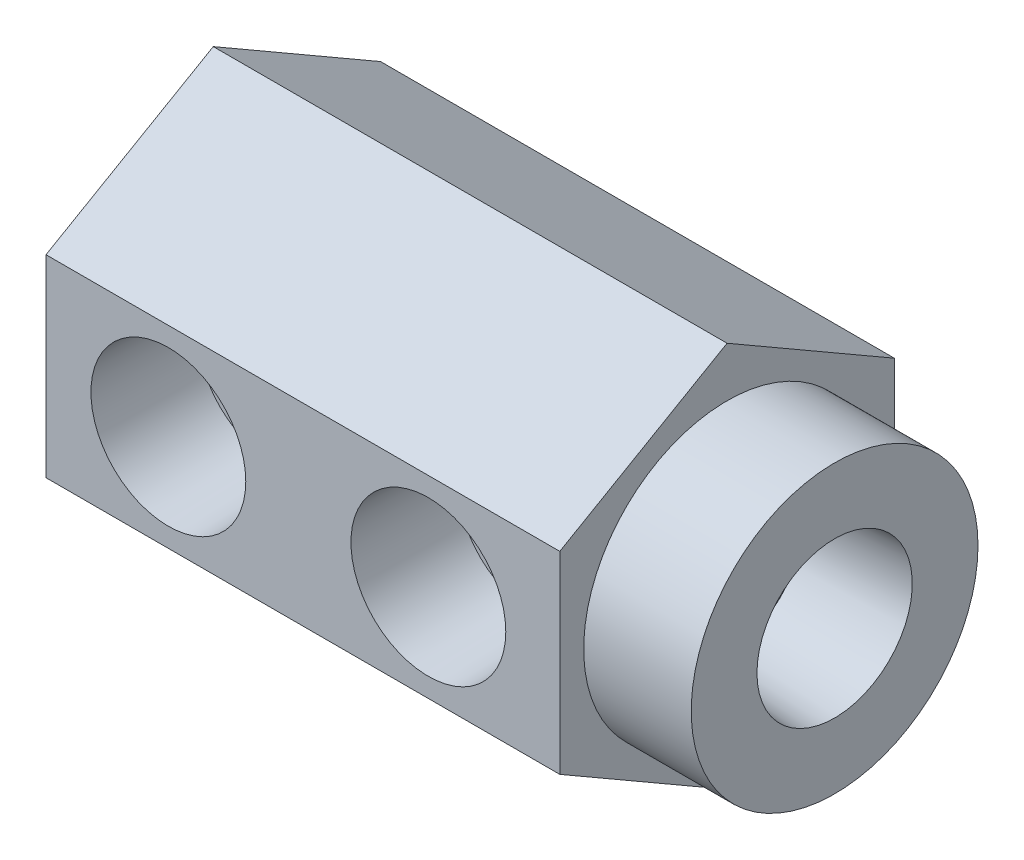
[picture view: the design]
ISO-10303-21;
HEADER;
FILE_DESCRIPTION(('STEP AP214'),'2;1');
FILE_NAME('part.step','',(''),(''),'','','');
FILE_SCHEMA(('AUTOMOTIVE_DESIGN { 1 0 10303 214 1 1 1 1 }'));
ENDSEC;
DATA;
#1=APPLICATION_CONTEXT('core data for automotive mechanical design processes');
#2=APPLICATION_PROTOCOL_DEFINITION('international standard','automotive_design',2000,#1);
#3=PRODUCT_CONTEXT('',#1,'mechanical');
#4=PRODUCT('Part','Part','',(#3));
#5=PRODUCT_RELATED_PRODUCT_CATEGORY('part','',(#4));
#6=PRODUCT_DEFINITION_FORMATION('','',#4);
#7=PRODUCT_DEFINITION_CONTEXT('part definition',#1,'design');
#8=PRODUCT_DEFINITION('design','',#6,#7);
#9=PRODUCT_DEFINITION_SHAPE('','',#8);
#10=(LENGTH_UNIT() NAMED_UNIT(*) SI_UNIT(.MILLI.,.METRE.));
#11=(NAMED_UNIT(*) PLANE_ANGLE_UNIT() SI_UNIT($,.RADIAN.));
#12=(NAMED_UNIT(*) SI_UNIT($,.STERADIAN.) SOLID_ANGLE_UNIT());
#13=UNCERTAINTY_MEASURE_WITH_UNIT(LENGTH_MEASURE(1.E-05),#10,'distance_accuracy_value','');
#14=(GEOMETRIC_REPRESENTATION_CONTEXT(3) GLOBAL_UNCERTAINTY_ASSIGNED_CONTEXT((#13)) GLOBAL_UNIT_ASSIGNED_CONTEXT((#10,
#11,#12)) REPRESENTATION_CONTEXT('',''));
#15=CARTESIAN_POINT('',(0.,0.,0.));
#16=DIRECTION('',(0.,0.,1.));
#17=DIRECTION('',(1.,0.,0.));
#18=AXIS2_PLACEMENT_3D('',#15,#16,#17);
#19=CARTESIAN_POINT('',(25.4,0.,0.));
#20=DIRECTION('',(1.,0.,0.));
#21=DIRECTION('',(0.,0.,-1.));
#22=AXIS2_PLACEMENT_3D('',#19,#20,#21);
#23=PLANE('',#22);
#24=DIRECTION('',(0.,0.,1.));
#25=VECTOR('',#24,1.);
#26=CARTESIAN_POINT('',(25.4,4.2164,11.1125));
#27=LINE('',#26,#25);
#28=CARTESIAN_POINT('',(25.4,4.2164,-1.14384635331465));
#29=VERTEX_POINT('',#28);
#30=CARTESIAN_POINT('',(25.4,4.2164,1.14384635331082));
#31=VERTEX_POINT('',#30);
#32=EDGE_CURVE('E248',#29,#31,#27,.T.);
#33=ORIENTED_EDGE('',*,*,#32,.F.);
#34=CARTESIAN_POINT('',(25.4,0.,0.));
#35=DIRECTION('',(-1.,0.,0.));
#36=DIRECTION('',(0.,0.,1.));
#37=AXIS2_PLACEMENT_3D('',#34,#35,#36);
#38=CIRCLE('',#37,4.36879999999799);
#39=EDGE_CURVE('E251',#31,#29,#38,.T.);
#40=ORIENTED_EDGE('',*,*,#39,.F.);
#41=EDGE_LOOP('',(#33,#40));
#42=FACE_BOUND('',#41,.T.);
#43=ADVANCED_FACE('F34',(#42),#23,.T.);
#44=CARTESIAN_POINT('',(41.275,0.,0.));
#45=DIRECTION('',(1.,0.,0.));
#46=DIRECTION('',(0.,0.,-1.));
#47=AXIS2_PLACEMENT_3D('',#44,#45,#46);
#48=PLANE('',#47);
#49=CARTESIAN_POINT('',(41.275,0.,0.));
#50=DIRECTION('',(1.,0.,0.));
#51=DIRECTION('',(0.,0.,-1.));
#52=AXIS2_PLACEMENT_3D('',#49,#50,#51);
#53=CIRCLE('',#52,9.525);
#54=CARTESIAN_POINT('',(41.275,0.,-9.525));
#55=VERTEX_POINT('',#54);
#56=EDGE_CURVE('E278',#55,#55,#53,.T.);
#57=ORIENTED_EDGE('',*,*,#56,.T.);
#58=EDGE_LOOP('',(#57));
#59=FACE_BOUND('',#58,.T.);
#60=CARTESIAN_POINT('',(41.275,0.,0.));
#61=DIRECTION('',(-1.,0.,0.));
#62=DIRECTION('',(0.,0.,1.));
#63=AXIS2_PLACEMENT_3D('',#60,#61,#62);
#64=CIRCLE('',#63,5.15886231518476);
#65=CARTESIAN_POINT('',(41.275,0.,5.15886231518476));
#66=VERTEX_POINT('',#65);
#67=EDGE_CURVE('E275',#66,#66,#64,.T.);
#68=ORIENTED_EDGE('',*,*,#67,.T.);
#69=EDGE_LOOP('',(#68));
#70=FACE_BOUND('',#69,.T.);
#71=ADVANCED_FACE('F237',(#59,#70),#48,.T.);
#72=CARTESIAN_POINT('',(34.13125,6.41580486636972,11.1125));
#73=DIRECTION('',(1.,0.,0.));
#74=DIRECTION('',(0.,0.,-1.));
#75=AXIS2_PLACEMENT_3D('',#72,#73,#74);
#76=PLANE('',#75);
#77=DIRECTION('',(0.,-0.5,0.866025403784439));
#78=VECTOR('',#77,1.);
#79=CARTESIAN_POINT('',(34.13125,12.8316097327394,0.));
#80=LINE('',#79,#78);
#81=CARTESIAN_POINT('',(34.13125,12.8316097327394,0.));
#82=VERTEX_POINT('',#81);
#83=CARTESIAN_POINT('',(34.13125,6.41580486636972,11.1125));
#84=VERTEX_POINT('',#83);
#85=EDGE_CURVE('E146',#82,#84,#80,.T.);
#86=ORIENTED_EDGE('',*,*,#85,.T.);
#87=DIRECTION('',(0.,-1.,0.));
#88=VECTOR('',#87,1.);
#89=CARTESIAN_POINT('',(34.13125,6.41580486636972,11.1125));
#90=LINE('',#89,#88);
#91=CARTESIAN_POINT('',(34.13125,-6.41580486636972,11.1125));
#92=VERTEX_POINT('',#91);
#93=EDGE_CURVE('E96',#84,#92,#90,.T.);
#94=ORIENTED_EDGE('',*,*,#93,.T.);
#95=DIRECTION('',(0.,-0.5,-0.866025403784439));
#96=VECTOR('',#95,1.);
#97=CARTESIAN_POINT('',(34.13125,-6.41580486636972,11.1125));
#98=LINE('',#97,#96);
#99=CARTESIAN_POINT('',(34.13125,-12.8316097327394,0.));
#100=VERTEX_POINT('',#99);
#101=EDGE_CURVE('E113',#92,#100,#98,.T.);
#102=ORIENTED_EDGE('',*,*,#101,.T.);
#103=DIRECTION('',(0.,0.5,-0.866025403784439));
#104=VECTOR('',#103,1.);
#105=CARTESIAN_POINT('',(34.13125,-12.8316097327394,0.));
#106=LINE('',#105,#104);
#107=CARTESIAN_POINT('',(34.13125,-6.41580486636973,-11.1125));
#108=VERTEX_POINT('',#107);
#109=EDGE_CURVE('E105',#100,#108,#106,.T.);
#110=ORIENTED_EDGE('',*,*,#109,.T.);
#111=DIRECTION('',(0.,1.,0.));
#112=VECTOR('',#111,1.);
#113=CARTESIAN_POINT('',(34.13125,-6.41580486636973,-11.1125));
#114=LINE('',#113,#112);
#115=CARTESIAN_POINT('',(34.13125,6.41580486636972,-11.1125));
#116=VERTEX_POINT('',#115);
#117=EDGE_CURVE('E110',#108,#116,#114,.T.);
#118=ORIENTED_EDGE('',*,*,#117,.T.);
#119=DIRECTION('',(0.,0.5,0.866025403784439));
#120=VECTOR('',#119,1.);
#121=CARTESIAN_POINT('',(34.13125,6.41580486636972,-11.1125));
#122=LINE('',#121,#120);
#123=EDGE_CURVE('E60',#116,#82,#122,.T.);
#124=ORIENTED_EDGE('',*,*,#123,.T.);
#125=EDGE_LOOP('',(#86,#94,#102,#110,#118,#124));
#126=FACE_BOUND('',#125,.T.);
#127=CARTESIAN_POINT('',(34.13125,0.,0.));
#128=DIRECTION('',(1.,0.,0.));
#129=DIRECTION('',(0.,0.,-1.));
#130=AXIS2_PLACEMENT_3D('',#127,#128,#129);
#131=CIRCLE('',#130,9.525);
#132=CARTESIAN_POINT('',(34.13125,0.,-9.525));
#133=VERTEX_POINT('',#132);
#134=EDGE_CURVE('E138',#133,#133,#131,.F.);
#135=ORIENTED_EDGE('',*,*,#134,.T.);
#136=EDGE_LOOP('',(#135));
#137=FACE_BOUND('',#136,.T.);
#138=ADVANCED_FACE('F107',(#126,#137),#76,.T.);
#139=CARTESIAN_POINT('',(34.13125,12.8316097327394,0.));
#140=DIRECTION('',(0.,-0.866025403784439,-0.5));
#141=DIRECTION('',(0.,0.5,-0.866025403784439));
#142=AXIS2_PLACEMENT_3D('',#139,#140,#141);
#143=PLANE('',#142);
#144=DIRECTION('',(0.,-0.5,0.866025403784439));
#145=VECTOR('',#144,1.);
#146=CARTESIAN_POINT('',(0.,12.8316097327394,0.));
#147=LINE('',#146,#145);
#148=CARTESIAN_POINT('',(0.,12.8316097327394,0.));
#149=VERTEX_POINT('',#148);
#150=CARTESIAN_POINT('',(0.,6.41580486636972,11.1125));
#151=VERTEX_POINT('',#150);
#152=EDGE_CURVE('E134',#149,#151,#147,.T.);
#153=ORIENTED_EDGE('',*,*,#152,.T.);
#154=DIRECTION('',(-1.,0.,0.));
#155=VECTOR('',#154,1.);
#156=CARTESIAN_POINT('',(34.13125,6.41580486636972,11.1125));
#157=LINE('',#156,#155);
#158=EDGE_CURVE('E153',#84,#151,#157,.T.);
#159=ORIENTED_EDGE('',*,*,#158,.F.);
#160=ORIENTED_EDGE('',*,*,#85,.F.);
#161=DIRECTION('',(-1.,0.,0.));
#162=VECTOR('',#161,1.);
#163=CARTESIAN_POINT('',(34.13125,12.8316097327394,0.));
#164=LINE('',#163,#162);
#165=EDGE_CURVE('E130',#82,#149,#164,.T.);
#166=ORIENTED_EDGE('',*,*,#165,.T.);
#167=EDGE_LOOP('',(#153,#159,#160,#166));
#168=FACE_BOUND('',#167,.T.);
#169=ADVANCED_FACE('F36',(#168),#143,.F.);
#170=CARTESIAN_POINT('',(34.13125,6.41580486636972,11.1125));
#171=DIRECTION('',(0.,0.,-1.));
#172=DIRECTION('',(0.,1.,0.));
#173=AXIS2_PLACEMENT_3D('',#170,#171,#172);
#174=PLANE('',#173);
#175=CARTESIAN_POINT('',(8.128,0.,11.1125));
#176=DIRECTION('',(0.,0.,1.));
#177=DIRECTION('',(1.,0.,0.));
#178=AXIS2_PLACEMENT_3D('',#175,#176,#177);
#179=CIRCLE('',#178,5.1435);
#180=CARTESIAN_POINT('',(13.2715,0.,11.1125));
#181=VERTEX_POINT('',#180);
#182=EDGE_CURVE('E219',#181,#181,#179,.T.);
#183=ORIENTED_EDGE('',*,*,#182,.F.);
#184=EDGE_LOOP('',(#183));
#185=FACE_BOUND('',#184,.T.);
#186=CARTESIAN_POINT('',(25.4,0.,11.1125));
#187=DIRECTION('',(0.,0.,1.));
#188=DIRECTION('',(1.,0.,0.));
#189=AXIS2_PLACEMENT_3D('',#186,#187,#188);
#190=CIRCLE('',#189,5.1435);
#191=CARTESIAN_POINT('',(30.5435,0.,11.1125));
#192=VERTEX_POINT('',#191);
#193=EDGE_CURVE('E482',#192,#192,#190,.T.);
#194=ORIENTED_EDGE('',*,*,#193,.F.);
#195=EDGE_LOOP('',(#194));
#196=FACE_BOUND('',#195,.T.);
#197=DIRECTION('',(0.,-1.,0.));
#198=VECTOR('',#197,1.);
#199=CARTESIAN_POINT('',(0.,6.41580486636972,11.1125));
#200=LINE('',#199,#198);
#201=CARTESIAN_POINT('',(0.,-6.41580486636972,11.1125));
#202=VERTEX_POINT('',#201);
#203=EDGE_CURVE('E137',#151,#202,#200,.T.);
#204=ORIENTED_EDGE('',*,*,#203,.T.);
#205=DIRECTION('',(-1.,0.,0.));
#206=VECTOR('',#205,1.);
#207=CARTESIAN_POINT('',(34.13125,-6.41580486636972,11.1125));
#208=LINE('',#207,#206);
#209=EDGE_CURVE('E150',#92,#202,#208,.T.);
#210=ORIENTED_EDGE('',*,*,#209,.F.);
#211=ORIENTED_EDGE('',*,*,#93,.F.);
#212=ORIENTED_EDGE('',*,*,#158,.T.);
#213=EDGE_LOOP('',(#204,#210,#211,#212));
#214=FACE_BOUND('',#213,.T.);
#215=ADVANCED_FACE('F286',(#185,#196,#214),#174,.F.);
#216=CARTESIAN_POINT('',(34.13125,-6.41580486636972,11.1125));
#217=DIRECTION('',(0.,0.866025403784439,-0.5));
#218=DIRECTION('',(0.,0.5,0.866025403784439));
#219=AXIS2_PLACEMENT_3D('',#216,#217,#218);
#220=PLANE('',#219);
#221=DIRECTION('',(0.,-0.5,-0.866025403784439));
#222=VECTOR('',#221,1.);
#223=CARTESIAN_POINT('',(0.,-6.41580486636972,11.1125));
#224=LINE('',#223,#222);
#225=CARTESIAN_POINT('',(0.,-12.8316097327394,0.));
#226=VERTEX_POINT('',#225);
#227=EDGE_CURVE('E140',#202,#226,#224,.T.);
#228=ORIENTED_EDGE('',*,*,#227,.T.);
#229=DIRECTION('',(-1.,0.,0.));
#230=VECTOR('',#229,1.);
#231=CARTESIAN_POINT('',(34.13125,-12.8316097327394,0.));
#232=LINE('',#231,#230);
#233=EDGE_CURVE('E125',#100,#226,#232,.T.);
#234=ORIENTED_EDGE('',*,*,#233,.F.);
#235=ORIENTED_EDGE('',*,*,#101,.F.);
#236=ORIENTED_EDGE('',*,*,#209,.T.);
#237=EDGE_LOOP('',(#228,#234,#235,#236));
#238=FACE_BOUND('',#237,.T.);
#239=ADVANCED_FACE('F289',(#238),#220,.F.);
#240=CARTESIAN_POINT('',(34.13125,-12.8316097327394,0.));
#241=DIRECTION('',(0.,0.866025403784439,0.5));
#242=DIRECTION('',(0.,-0.5,0.866025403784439));
#243=AXIS2_PLACEMENT_3D('',#240,#241,#242);
#244=PLANE('',#243);
#245=DIRECTION('',(0.,0.5,-0.866025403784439));
#246=VECTOR('',#245,1.);
#247=CARTESIAN_POINT('',(0.,-12.8316097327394,0.));
#248=LINE('',#247,#246);
#249=CARTESIAN_POINT('',(0.,-6.41580486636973,-11.1125));
#250=VERTEX_POINT('',#249);
#251=EDGE_CURVE('E122',#226,#250,#248,.T.);
#252=ORIENTED_EDGE('',*,*,#251,.T.);
#253=DIRECTION('',(-1.,0.,0.));
#254=VECTOR('',#253,1.);
#255=CARTESIAN_POINT('',(34.13125,-6.41580486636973,-11.1125));
#256=LINE('',#255,#254);
#257=EDGE_CURVE('E119',#108,#250,#256,.T.);
#258=ORIENTED_EDGE('',*,*,#257,.F.);
#259=ORIENTED_EDGE('',*,*,#109,.F.);
#260=ORIENTED_EDGE('',*,*,#233,.T.);
#261=EDGE_LOOP('',(#252,#258,#259,#260));
#262=FACE_BOUND('',#261,.T.);
#263=ADVANCED_FACE('F120',(#262),#244,.F.);
#264=CARTESIAN_POINT('',(34.13125,-6.41580486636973,-11.1125));
#265=DIRECTION('',(0.,0.,1.));
#266=DIRECTION('',(1.,0.,0.));
#267=AXIS2_PLACEMENT_3D('',#264,#265,#266);
#268=PLANE('',#267);
#269=CARTESIAN_POINT('',(8.128,0.,-11.1125));
#270=DIRECTION('',(0.,0.,-1.));
#271=DIRECTION('',(-1.,0.,0.));
#272=AXIS2_PLACEMENT_3D('',#269,#270,#271);
#273=CIRCLE('',#272,5.3164359);
#274=CARTESIAN_POINT('',(2.8115641,0.,-11.1125));
#275=VERTEX_POINT('',#274);
#276=EDGE_CURVE('E255',#275,#275,#273,.T.);
#277=ORIENTED_EDGE('',*,*,#276,.F.);
#278=EDGE_LOOP('',(#277));
#279=FACE_BOUND('',#278,.T.);
#280=DIRECTION('',(0.,1.,0.));
#281=VECTOR('',#280,1.);
#282=CARTESIAN_POINT('',(0.,-6.41580486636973,-11.1125));
#283=LINE('',#282,#281);
#284=CARTESIAN_POINT('',(0.,6.41580486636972,-11.1125));
#285=VERTEX_POINT('',#284);
#286=EDGE_CURVE('E143',#250,#285,#283,.T.);
#287=ORIENTED_EDGE('',*,*,#286,.T.);
#288=DIRECTION('',(-1.,0.,0.));
#289=VECTOR('',#288,1.);
#290=CARTESIAN_POINT('',(34.13125,6.41580486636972,-11.1125));
#291=LINE('',#290,#289);
#292=EDGE_CURVE('E126',#116,#285,#291,.T.);
#293=ORIENTED_EDGE('',*,*,#292,.F.);
#294=ORIENTED_EDGE('',*,*,#117,.F.);
#295=ORIENTED_EDGE('',*,*,#257,.T.);
#296=EDGE_LOOP('',(#287,#293,#294,#295));
#297=FACE_BOUND('',#296,.T.);
#298=ADVANCED_FACE('F128',(#279,#297),#268,.F.);
#299=CARTESIAN_POINT('',(34.13125,6.41580486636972,-11.1125));
#300=DIRECTION('',(0.,-0.866025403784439,0.5));
#301=DIRECTION('',(0.,-0.5,-0.866025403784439));
#302=AXIS2_PLACEMENT_3D('',#299,#300,#301);
#303=PLANE('',#302);
#304=DIRECTION('',(0.,0.5,0.866025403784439));
#305=VECTOR('',#304,1.);
#306=CARTESIAN_POINT('',(0.,6.41580486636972,-11.1125));
#307=LINE('',#306,#305);
#308=EDGE_CURVE('E87',#285,#149,#307,.T.);
#309=ORIENTED_EDGE('',*,*,#308,.T.);
#310=ORIENTED_EDGE('',*,*,#165,.F.);
#311=ORIENTED_EDGE('',*,*,#123,.F.);
#312=ORIENTED_EDGE('',*,*,#292,.T.);
#313=EDGE_LOOP('',(#309,#310,#311,#312));
#314=FACE_BOUND('',#313,.T.);
#315=ADVANCED_FACE('F293',(#314),#303,.F.);
#316=CARTESIAN_POINT('',(0.,6.41580486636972,11.1125));
#317=DIRECTION('',(1.,0.,0.));
#318=DIRECTION('',(0.,0.,-1.));
#319=AXIS2_PLACEMENT_3D('',#316,#317,#318);
#320=PLANE('',#319);
#321=ORIENTED_EDGE('',*,*,#152,.F.);
#322=ORIENTED_EDGE('',*,*,#308,.F.);
#323=ORIENTED_EDGE('',*,*,#286,.F.);
#324=ORIENTED_EDGE('',*,*,#251,.F.);
#325=ORIENTED_EDGE('',*,*,#227,.F.);
#326=ORIENTED_EDGE('',*,*,#203,.F.);
#327=EDGE_LOOP('',(#321,#322,#323,#324,#325,#326));
#328=FACE_BOUND('',#327,.T.);
#329=ADVANCED_FACE('F292',(#328),#320,.F.);
#330=CARTESIAN_POINT('',(41.275,0.,0.));
#331=DIRECTION('',(-1.,0.,0.));
#332=DIRECTION('',(0.,0.,1.));
#333=AXIS2_PLACEMENT_3D('',#330,#331,#332);
#334=CYLINDRICAL_SURFACE('',#333,9.525);
#335=ORIENTED_EDGE('',*,*,#134,.F.);
#336=EDGE_LOOP('',(#335));
#337=FACE_BOUND('',#336,.T.);
#338=ORIENTED_EDGE('',*,*,#56,.F.);
#339=EDGE_LOOP('',(#338));
#340=FACE_BOUND('',#339,.T.);
#341=ADVANCED_FACE('F306',(#337,#340),#334,.T.);
#342=CARTESIAN_POINT('',(41.275,0.,0.));
#343=DIRECTION('',(1.,0.,0.));
#344=DIRECTION('',(0.,0.,-1.));
#345=AXIS2_PLACEMENT_3D('',#342,#343,#344);
#346=CONICAL_SURFACE('',#345,5.15886231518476,0.0523598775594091);
#347=CARTESIAN_POINT('',(34.29,0.,0.));
#348=DIRECTION('',(-1.,0.,0.));
#349=DIRECTION('',(0.,0.,1.));
#350=AXIS2_PLACEMENT_3D('',#347,#348,#349);
#351=CIRCLE('',#350,4.79279397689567);
#352=CARTESIAN_POINT('',(34.29,0.,4.79279397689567));
#353=VERTEX_POINT('',#352);
#354=EDGE_CURVE('E267',#353,#353,#351,.T.);
#355=ORIENTED_EDGE('',*,*,#354,.T.);
#356=EDGE_LOOP('',(#355));
#357=FACE_BOUND('',#356,.T.);
#358=ORIENTED_EDGE('',*,*,#67,.F.);
#359=EDGE_LOOP('',(#358));
#360=FACE_BOUND('',#359,.T.);
#361=ADVANCED_FACE('F345',(#357,#360),#346,.F.);
#362=CARTESIAN_POINT('',(34.29,0.,-4.3688));
#363=DIRECTION('',(1.,0.,0.));
#364=DIRECTION('',(0.,0.,-1.));
#365=AXIS2_PLACEMENT_3D('',#362,#363,#364);
#366=PLANE('',#365);
#367=CARTESIAN_POINT('',(34.29,0.,0.));
#368=DIRECTION('',(-1.,0.,0.));
#369=DIRECTION('',(0.,0.,1.));
#370=AXIS2_PLACEMENT_3D('',#367,#368,#369);
#371=CIRCLE('',#370,4.3688);
#372=CARTESIAN_POINT('',(34.29,0.,4.3688));
#373=VERTEX_POINT('',#372);
#374=EDGE_CURVE('E263',#373,#373,#371,.T.);
#375=ORIENTED_EDGE('',*,*,#374,.T.);
#376=EDGE_LOOP('',(#375));
#377=FACE_BOUND('',#376,.T.);
#378=ORIENTED_EDGE('',*,*,#354,.F.);
#379=EDGE_LOOP('',(#378));
#380=FACE_BOUND('',#379,.T.);
#381=ADVANCED_FACE('F233',(#377,#380),#366,.T.);
#382=CARTESIAN_POINT('',(-4.01191983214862,0.,0.));
#383=DIRECTION('',(-1.,0.,0.));
#384=DIRECTION('',(0.,0.,1.));
#385=AXIS2_PLACEMENT_3D('',#382,#383,#384);
#386=CYLINDRICAL_SURFACE('',#385,4.36879999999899);
#387=CARTESIAN_POINT('',(25.4,-4.2164,-1.14384635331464));
#388=CARTESIAN_POINT('',(25.4382959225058,-4.21640509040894,-1.14380937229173));
#389=CARTESIAN_POINT('',(25.4765532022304,-4.21587815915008,-1.14577041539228));
#390=CARTESIAN_POINT('',(25.552565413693,-4.2138087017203,-1.15336705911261));
#391=CARTESIAN_POINT('',(25.5903214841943,-4.21226913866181,-1.15899193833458));
#392=CARTESIAN_POINT('',(25.7010377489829,-4.20628016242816,-1.18060825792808));
#393=CARTESIAN_POINT('',(25.7730026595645,-4.20045614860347,-1.20136776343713));
#394=CARTESIAN_POINT('',(25.9010959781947,-4.18692745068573,-1.24760620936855));
#395=CARTESIAN_POINT('',(25.9578264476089,-4.17971539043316,-1.27166887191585));
#396=CARTESIAN_POINT('',(26.0689520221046,-4.1633733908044,-1.32419771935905));
#397=CARTESIAN_POINT('',(26.1233452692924,-4.15424195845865,-1.35266732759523));
#398=CARTESIAN_POINT('',(26.284746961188,-4.12400027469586,-1.44328640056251));
#399=CARTESIAN_POINT('',(26.3886066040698,-4.10019771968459,-1.51007513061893));
#400=CARTESIAN_POINT('',(26.6094123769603,-4.04112930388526,-1.66240980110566));
#401=CARTESIAN_POINT('',(26.7251608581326,-4.004550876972,-1.74912466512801));
#402=CARTESIAN_POINT('',(26.950992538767,-3.92260860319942,-1.92589865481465));
#403=CARTESIAN_POINT('',(27.0610702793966,-3.87723648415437,-2.01596086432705));
#404=CARTESIAN_POINT('',(27.2761751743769,-3.77782789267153,-2.19659692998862));
#405=CARTESIAN_POINT('',(27.3812161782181,-3.72381718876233,-2.28716851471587));
#406=CARTESIAN_POINT('',(27.5868818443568,-3.60687682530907,-2.46746911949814));
#407=CARTESIAN_POINT('',(27.6875082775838,-3.5439507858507,-2.55719846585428));
#408=CARTESIAN_POINT('',(27.8839225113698,-3.40914667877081,-2.73431262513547));
#409=CARTESIAN_POINT('',(27.9797272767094,-3.3373036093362,-2.82170506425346));
#410=CARTESIAN_POINT('',(28.1664627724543,-3.18422748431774,-2.99338616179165));
#411=CARTESIAN_POINT('',(28.2573925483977,-3.10299259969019,-3.07767421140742));
#412=CARTESIAN_POINT('',(28.5217820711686,-2.8448347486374,-3.32412307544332));
#413=CARTESIAN_POINT('',(28.68722877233,-2.65319886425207,-3.4802217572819));
#414=CARTESIAN_POINT('',(28.946155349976,-2.28867585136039,-3.72591922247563));
#415=CARTESIAN_POINT('',(29.0468848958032,-2.12525740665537,-3.82197074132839));
#416=CARTESIAN_POINT('',(29.2280303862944,-1.77829965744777,-3.99518324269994));
#417=CARTESIAN_POINT('',(29.3084740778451,-1.59478833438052,-4.07237002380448));
#418=CARTESIAN_POINT('',(29.4335729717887,-1.24016971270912,-4.19259453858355));
#419=CARTESIAN_POINT('',(29.4818329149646,-1.07150882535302,-4.23906171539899));
#420=CARTESIAN_POINT('',(29.5573157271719,-0.725306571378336,-4.31179252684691));
#421=CARTESIAN_POINT('',(29.5845506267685,-0.547770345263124,-4.3380677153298));
#422=CARTESIAN_POINT('',(29.6160780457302,-0.188133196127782,-4.36848728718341));
#423=CARTESIAN_POINT('',(29.6202918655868,-0.00601875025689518,-4.37255575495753));
#424=CARTESIAN_POINT('',(29.6052294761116,0.356312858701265,-4.35801970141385));
#425=CARTESIAN_POINT('',(29.5859515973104,0.536529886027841,-4.33941356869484));
#426=CARTESIAN_POINT('',(29.5270019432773,0.880158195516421,-4.28257774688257));
#427=CARTESIAN_POINT('',(29.4884693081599,1.04395352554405,-4.24544432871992));
#428=CARTESIAN_POINT('',(29.3939743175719,1.36150296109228,-4.15452191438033));
#429=CARTESIAN_POINT('',(29.3380058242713,1.51525350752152,-4.10072705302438));
#430=CARTESIAN_POINT('',(29.1874242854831,1.86608787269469,-3.95630437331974));
#431=CARTESIAN_POINT('',(29.0861917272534,2.05776563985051,-3.85943081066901));
#432=CARTESIAN_POINT('',(28.8621173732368,2.41591223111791,-3.64602460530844));
#433=CARTESIAN_POINT('',(28.7392287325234,2.58232492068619,-3.52944936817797));
#434=CARTESIAN_POINT('',(28.4292865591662,2.94574331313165,-3.23746909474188));
#435=CARTESIAN_POINT('',(28.2351369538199,3.13191591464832,-3.05607279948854));
#436=CARTESIAN_POINT('',(27.9273645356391,3.37752954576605,-2.77386569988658));
#437=CARTESIAN_POINT('',(27.8219282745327,3.45383891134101,-2.67803363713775));
#438=CARTESIAN_POINT('',(27.6058304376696,3.59569760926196,-2.4843000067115));
#439=CARTESIAN_POINT('',(27.4951706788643,3.6612506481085,-2.38639916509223));
#440=CARTESIAN_POINT('',(27.3034156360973,3.76336891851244,-2.22032608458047));
#441=CARTESIAN_POINT('',(27.2236652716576,3.802657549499,-2.15224760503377));
#442=CARTESIAN_POINT('',(27.0614584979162,3.87627650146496,-2.01664021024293));
#443=CARTESIAN_POINT('',(26.9790024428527,3.91060746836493,-1.94911122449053));
#444=CARTESIAN_POINT('',(26.8108798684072,3.97436048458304,-1.81558453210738));
#445=CARTESIAN_POINT('',(26.7252107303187,4.00377841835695,-1.74958814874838));
#446=CARTESIAN_POINT('',(26.5499603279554,4.05758896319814,-1.62087320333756));
#447=CARTESIAN_POINT('',(26.4603817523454,4.08198496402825,-1.5581524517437));
#448=CARTESIAN_POINT('',(26.2863990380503,4.12303037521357,-1.44574995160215));
#449=CARTESIAN_POINT('',(26.2025707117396,4.14024606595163,-1.39539700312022));
#450=CARTESIAN_POINT('',(26.0299590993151,4.1699870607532,-1.30380280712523));
#451=CARTESIAN_POINT('',(25.9412226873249,4.18255009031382,-1.2624894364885));
#452=CARTESIAN_POINT('',(25.7781622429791,4.20001018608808,-1.20294863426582));
#453=CARTESIAN_POINT('',(25.705165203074,4.2060020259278,-1.18160521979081));
#454=CARTESIAN_POINT('',(25.592868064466,4.2121576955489,-1.15939760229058));
#455=CARTESIAN_POINT('',(25.554613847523,4.21373856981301,-1.15362350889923));
#456=CARTESIAN_POINT('',(25.4775866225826,4.2158639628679,-1.14582312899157));
#457=CARTESIAN_POINT('',(25.4388124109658,4.21640538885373,-1.14380802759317));
#458=CARTESIAN_POINT('',(25.3999999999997,4.21640000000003,-1.14384635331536));
#459=B_SPLINE_CURVE_WITH_KNOTS('',3,(#387,#388,#389,#390,#391,#392,#393,#394,#395,#396,#397,
#398,#399,#400,#401,#402,#403,#404,#405,#406,#407,#408,#409,#410,#411,#412,#413,#414,#415,#416,
#417,#418,#419,#420,#421,#422,#423,#424,#425,#426,#427,#428,#429,#430,#431,#432,#433,#434,#435,
#436,#437,#438,#439,#440,#441,#442,#443,#444,#445,#446,#447,#448,#449,#450,#451,#452,#453,#454,
#455,#456,#457,#458),.UNSPECIFIED.,.F.,.F.,(4,2,2,2,2,2,2,2,2,2,2,2,2,2,2,2,2,2,2,2,2,2,2,2,2,2,
2,2,2,2,2,2,2,2,2,4),(0.,0.114768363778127,0.229202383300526,0.453478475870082,
0.639361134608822,0.825388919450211,1.20188165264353,1.64896749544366,2.09647596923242,
2.54267362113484,2.98869061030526,3.43300933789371,3.87741474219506,4.76448895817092,
5.40626965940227,6.04716771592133,6.58930246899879,7.13112678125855,7.6748022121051,
8.21851628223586,8.73331387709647,9.24829289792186,9.95663818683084,10.6665349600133,
11.6342055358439,12.1187866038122,12.6032003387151,12.9390046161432,13.2747651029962,
13.6108054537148,13.9466182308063,14.2441145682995,14.539142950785,14.7669032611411,
14.8828759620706,14.9991932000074),.UNSPECIFIED.);
#460=CARTESIAN_POINT('',(25.4,-4.2164,-1.14384635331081));
#461=VERTEX_POINT('',#460);
#462=EDGE_CURVE('E11',#461,#29,#459,.T.);
#463=ORIENTED_EDGE('',*,*,#462,.F.);
#464=CARTESIAN_POINT('',(25.4,-4.2164,1.14384635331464));
#465=VERTEX_POINT('',#464);
#466=EDGE_CURVE('E264',#461,#465,#38,.T.);
#467=ORIENTED_EDGE('',*,*,#466,.T.);
#468=CARTESIAN_POINT('',(29.4292446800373,-1.24226256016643,4.18846));
#469=CARTESIAN_POINT('',(29.3952006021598,-1.35273289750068,4.15571214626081));
#470=CARTESIAN_POINT('',(29.3569523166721,-1.46061199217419,4.118946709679));
#471=CARTESIAN_POINT('',(29.2730241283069,-1.67045570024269,4.03838551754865));
#472=CARTESIAN_POINT('',(29.2273583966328,-1.77243109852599,3.99460317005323));
#473=CARTESIAN_POINT('',(29.1299690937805,-1.96908171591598,3.90139180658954));
#474=CARTESIAN_POINT('',(29.0783167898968,-2.06382425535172,3.85202936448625));
#475=CARTESIAN_POINT('',(28.9693395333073,-2.24704499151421,3.74810616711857));
#476=CARTESIAN_POINT('',(28.9120113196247,-2.33551953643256,3.69354242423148));
#477=CARTESIAN_POINT('',(28.7777414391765,-2.52699800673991,3.56608628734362));
#478=CARTESIAN_POINT('',(28.6994385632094,-2.6282408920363,3.49198149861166));
#479=CARTESIAN_POINT('',(28.5363557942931,-2.82085690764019,3.33831768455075));
#480=CARTESIAN_POINT('',(28.4515748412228,-2.91222841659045,3.25875776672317));
#481=CARTESIAN_POINT('',(28.275998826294,-3.08577014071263,3.09495512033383));
#482=CARTESIAN_POINT('',(28.1851741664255,-3.16788881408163,3.01068972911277));
#483=CARTESIAN_POINT('',(27.9986240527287,-3.32262985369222,2.83899583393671));
#484=CARTESIAN_POINT('',(27.9028992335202,-3.39525344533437,2.75156774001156));
#485=CARTESIAN_POINT('',(27.7047576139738,-3.532845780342,2.57263183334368));
#486=CARTESIAN_POINT('',(27.6022385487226,-3.59760480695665,2.4810764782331));
#487=CARTESIAN_POINT('',(27.3926047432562,-3.71781764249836,2.29702441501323));
#488=CARTESIAN_POINT('',(27.285488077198,-3.77326750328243,2.20452732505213));
#489=CARTESIAN_POINT('',(27.0666673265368,-3.87488965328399,2.02055799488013));
#490=CARTESIAN_POINT('',(26.9549765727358,-3.92108687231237,1.92908364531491));
#491=CARTESIAN_POINT('',(26.7257391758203,-4.00441579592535,1.74951137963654));
#492=CARTESIAN_POINT('',(26.6081985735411,-4.04155662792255,1.66141014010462));
#493=CARTESIAN_POINT('',(26.4005115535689,-4.09693829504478,1.51840665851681));
#494=CARTESIAN_POINT('',(26.3124794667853,-4.117524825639,1.46136281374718));
#495=CARTESIAN_POINT('',(26.1305999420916,-4.15365440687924,1.35523938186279));
#496=CARTESIAN_POINT('',(26.0367579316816,-4.16920208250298,1.30615251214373));
#497=CARTESIAN_POINT('',(25.8707386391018,-4.19060826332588,1.23537856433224));
#498=CARTESIAN_POINT('',(25.8004332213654,-4.19797337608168,1.20988515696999));
#499=CARTESIAN_POINT('',(25.6565333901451,-4.2091968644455,1.17027071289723));
#500=CARTESIAN_POINT('',(25.5829563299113,-4.21307185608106,1.1560958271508));
#501=CARTESIAN_POINT('',(25.4725911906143,-4.21593553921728,1.14554893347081));
#502=CARTESIAN_POINT('',(25.4363084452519,-4.21641147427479,1.14377318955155));
#503=CARTESIAN_POINT('',(25.4,-4.2164,1.14384635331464));
#504=B_SPLINE_CURVE_WITH_KNOTS('',3,(#468,#469,#470,#471,#472,#473,#474,#475,#476,#477,#478,
#479,#480,#481,#482,#483,#484,#485,#486,#487,#488,#489,#490,#491,#492,#493,#494,#495,#496,#497,
#498,#499,#500,#501,#502,#503),.UNSPECIFIED.,.F.,.F.,(4,2,2,2,2,2,2,2,2,2,2,2,2,2,2,2,2,4),(0.,
0.36013207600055,0.719584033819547,1.07512758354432,1.43087660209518,1.87390808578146,
2.31701222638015,2.7624738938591,3.20787801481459,3.66333295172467,4.11898056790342,
4.57338348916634,5.02732653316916,5.3477180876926,5.66781472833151,5.89257483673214,
6.11625914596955,6.22510746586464),.UNSPECIFIED.);
#505=CARTESIAN_POINT('',(29.4292446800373,-1.24226256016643,4.18846));
#506=VERTEX_POINT('',#505);
#507=EDGE_CURVE('E155',#506,#465,#504,.T.);
#508=ORIENTED_EDGE('',*,*,#507,.F.);
#509=DIRECTION('',(-1.,0.,0.));
#510=VECTOR('',#509,1.);
#511=CARTESIAN_POINT('',(-4.01191983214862,-1.24226256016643,4.18846));
#512=LINE('',#511,#510);
#513=CARTESIAN_POINT('',(30.177311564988,-1.24226256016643,4.18846));
#514=VERTEX_POINT('',#513);
#515=EDGE_CURVE('E162',#514,#506,#512,.T.);
#516=ORIENTED_EDGE('',*,*,#515,.F.);
#517=CARTESIAN_POINT('',(30.1771300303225,1.24293668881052,4.18826));
#518=CARTESIAN_POINT('',(30.200607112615,1.15583523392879,4.21412336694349));
#519=CARTESIAN_POINT('',(30.2217868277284,1.06732839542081,4.23741836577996));
#520=CARTESIAN_POINT('',(30.2592560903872,0.888007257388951,4.27858516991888));
#521=CARTESIAN_POINT('',(30.2755434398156,0.797191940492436,4.2964545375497));
#522=CARTESIAN_POINT('',(30.302904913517,0.613876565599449,4.32645329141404));
#523=CARTESIAN_POINT('',(30.313981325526,0.521377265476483,4.33858519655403));
#524=CARTESIAN_POINT('',(30.3307218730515,0.335324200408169,4.35691457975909));
#525=CARTESIAN_POINT('',(30.3363871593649,0.241770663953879,4.36311331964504));
#526=CARTESIAN_POINT('',(30.3422050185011,0.0540097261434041,4.36947895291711));
#527=CARTESIAN_POINT('',(30.3423413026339,-0.0401987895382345,4.36962802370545));
#528=CARTESIAN_POINT('',(30.3370571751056,-0.228273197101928,4.36384645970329));
#529=CARTESIAN_POINT('',(30.3316366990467,-0.322139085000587,4.35791575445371));
#530=CARTESIAN_POINT('',(30.3153617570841,-0.508659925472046,4.34009705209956));
#531=CARTESIAN_POINT('',(30.3045165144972,-0.601316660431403,4.32821916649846));
#532=CARTESIAN_POINT('',(30.2776075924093,-0.784900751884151,4.29871858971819));
#533=CARTESIAN_POINT('',(30.2615464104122,-0.875828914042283,4.28109864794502));
#534=CARTESIAN_POINT('',(30.2333463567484,-1.01252796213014,4.25011977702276));
#535=CARTESIAN_POINT('',(30.2229951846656,-1.05913454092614,4.23874207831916));
#536=CARTESIAN_POINT('',(30.2010123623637,-1.15159574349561,4.21456055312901));
#537=CARTESIAN_POINT('',(30.1893825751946,-1.19745135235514,4.2017588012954));
#538=CARTESIAN_POINT('',(30.1771300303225,-1.24293668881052,4.18826));
#539=B_SPLINE_CURVE_WITH_KNOTS('',3,(#517,#518,#519,#520,#521,#522,#523,#524,#525,#526,#527,
#528,#529,#530,#531,#532,#533,#534,#535,#536,#537,#538),.UNSPECIFIED.,.F.,.F.,(4,2,2,2,2,2,2,2,
2,2,4),(0.,0.28149265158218,0.563111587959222,0.844606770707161,1.12604207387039,
1.40830643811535,1.69057407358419,1.97236341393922,2.25401802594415,2.40121826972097,
2.54820680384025),.UNSPECIFIED.);
#540=CARTESIAN_POINT('',(30.177311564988,1.24226256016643,4.18846));
#541=VERTEX_POINT('',#540);
#542=EDGE_CURVE('E511',#541,#514,#539,.T.);
#543=ORIENTED_EDGE('',*,*,#542,.F.);
#544=DIRECTION('',(-1.,0.,0.));
#545=VECTOR('',#544,1.);
#546=CARTESIAN_POINT('',(-4.01191983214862,1.24226256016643,4.18846));
#547=LINE('',#546,#545);
#548=CARTESIAN_POINT('',(29.4292446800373,1.24226256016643,4.18846));
#549=VERTEX_POINT('',#548);
#550=EDGE_CURVE('E508',#549,#541,#547,.F.);
#551=ORIENTED_EDGE('',*,*,#550,.F.);
#552=CARTESIAN_POINT('',(25.4,4.2164,1.14384635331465));
#553=CARTESIAN_POINT('',(25.4382946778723,4.21640508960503,1.14380937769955));
#554=CARTESIAN_POINT('',(25.4765507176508,4.21587819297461,1.14577029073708));
#555=CARTESIAN_POINT('',(25.5525604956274,4.21380886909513,1.15336644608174));
#556=CARTESIAN_POINT('',(25.5903153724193,4.2122694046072,1.15899096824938));
#557=CARTESIAN_POINT('',(25.7010329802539,4.20628054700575,1.18060688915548));
#558=CARTESIAN_POINT('',(25.7730003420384,4.20045639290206,1.20136692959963));
#559=CARTESIAN_POINT('',(25.9010994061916,4.1869270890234,1.2476074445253));
#560=CARTESIAN_POINT('',(25.957833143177,4.17971453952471,1.27167170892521));
#561=CARTESIAN_POINT('',(26.0689649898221,4.16337135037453,1.32420417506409));
#562=CARTESIAN_POINT('',(26.1233612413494,4.15423921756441,1.35267580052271));
#563=CARTESIAN_POINT('',(26.2847590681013,4.12399749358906,1.44329421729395));
#564=CARTESIAN_POINT('',(26.3886125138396,4.10019613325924,1.51007919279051));
#565=CARTESIAN_POINT('',(26.6093729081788,4.04113986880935,1.66238258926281));
#566=CARTESIAN_POINT('',(26.7250845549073,4.00457500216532,1.74906763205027));
#567=CARTESIAN_POINT('',(26.9508454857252,3.92266551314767,1.92578088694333));
#568=CARTESIAN_POINT('',(27.0608893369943,3.87731265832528,2.01581216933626));
#569=CARTESIAN_POINT('',(27.2759989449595,3.77791674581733,2.19644572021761));
#570=CARTESIAN_POINT('',(27.3810754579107,3.72389369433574,2.28704622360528));
#571=CARTESIAN_POINT('',(27.5868141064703,3.60691884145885,2.4674086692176));
#572=CARTESIAN_POINT('',(27.6874779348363,3.5439705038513,2.55717092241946));
#573=CARTESIAN_POINT('',(27.8840648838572,3.40905006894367,2.73444118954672));
#574=CARTESIAN_POINT('',(27.9799999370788,3.33710249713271,2.82195457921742));
#575=CARTESIAN_POINT('',(28.1670159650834,3.18375149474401,2.99389591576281));
#576=CARTESIAN_POINT('',(28.258096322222,3.10234686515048,3.07832346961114));
#577=CARTESIAN_POINT('',(28.4343799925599,2.93013512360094,3.24265865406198));
#578=CARTESIAN_POINT('',(28.5196042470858,2.83936476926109,3.32258218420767));
#579=CARTESIAN_POINT('',(28.6836373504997,2.64794904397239,3.47705316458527));
#580=CARTESIAN_POINT('',(28.7624470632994,2.54730500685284,3.55160133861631));
#581=CARTESIAN_POINT('',(28.8989104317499,2.35518817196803,3.68108458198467));
#582=CARTESIAN_POINT('',(28.9578122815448,2.26534949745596,3.73712818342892));
#583=CARTESIAN_POINT('',(29.0697477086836,2.07912888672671,3.8438454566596));
#584=CARTESIAN_POINT('',(29.1227847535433,1.9827508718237,3.89452230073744));
#585=CARTESIAN_POINT('',(29.2226917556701,1.78260449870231,3.99013074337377));
#586=CARTESIAN_POINT('',(29.2694922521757,1.67877001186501,4.03499749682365));
#587=CARTESIAN_POINT('',(29.355411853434,1.46495258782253,4.11746606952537));
#588=CARTESIAN_POINT('',(29.3945155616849,1.35495788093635,4.15505332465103));
#589=CARTESIAN_POINT('',(29.4292446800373,1.24226256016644,4.18846));
#590=B_SPLINE_CURVE_WITH_KNOTS('',3,(#552,#553,#554,#555,#556,#557,#558,#559,#560,#561,#562,
#563,#564,#565,#566,#567,#568,#569,#570,#571,#572,#573,#574,#575,#576,#577,#578,#579,#580,#581,
#582,#583,#584,#585,#586,#587,#588,#589),.UNSPECIFIED.,.F.,.F.,(4,2,2,2,2,2,2,2,2,2,2,2,2,2,2,2,
2,2,4),(0.,0.114764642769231,0.229194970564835,0.453478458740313,0.639372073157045,
0.825410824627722,1.20188165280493,1.64882044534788,2.09617996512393,2.54252167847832,
2.98869064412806,3.43366913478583,3.8787041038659,4.32205448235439,4.76534505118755,
5.12845015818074,5.49133942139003,5.85798208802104,6.22535088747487),.UNSPECIFIED.);
#591=EDGE_CURVE('E43',#31,#549,#590,.T.);
#592=ORIENTED_EDGE('',*,*,#591,.F.);
#593=ORIENTED_EDGE('',*,*,#39,.T.);
#594=EDGE_LOOP('',(#463,#467,#508,#516,#543,#551,#592,#593));
#595=FACE_BOUND('',#594,.T.);
#596=ORIENTED_EDGE('',*,*,#374,.F.);
#597=EDGE_LOOP('',(#596));
#598=FACE_BOUND('',#597,.T.);
#599=ADVANCED_FACE('F164',(#595,#598),#386,.F.);
#600=DIRECTION('',(0.,0.,1.));
#601=VECTOR('',#600,1.);
#602=CARTESIAN_POINT('',(25.4,-4.2164,11.1125));
#603=LINE('',#602,#601);
#604=EDGE_CURVE('E256',#465,#461,#603,.F.);
#605=ORIENTED_EDGE('',*,*,#604,.F.);
#606=ORIENTED_EDGE('',*,*,#466,.F.);
#607=EDGE_LOOP('',(#605,#606));
#608=FACE_BOUND('',#607,.T.);
#609=ADVANCED_FACE('F226',(#608),#23,.T.);
#610=CARTESIAN_POINT('',(8.128,0.,-11.1125));
#611=DIRECTION('',(0.,0.,-1.));
#612=DIRECTION('',(-1.,0.,0.));
#613=AXIS2_PLACEMENT_3D('',#610,#611,#612);
#614=CYLINDRICAL_SURFACE('',#613,4.2164);
#615=CARTESIAN_POINT('',(12.3444,0.,-2.01929999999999));
#616=CARTESIAN_POINT('',(12.3443947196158,0.106687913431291,-2.01929379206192));
#617=CARTESIAN_POINT('',(12.3403065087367,0.213518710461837,-2.01079506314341));
#618=CARTESIAN_POINT('',(12.324356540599,0.424056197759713,-1.97716034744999));
#619=CARTESIAN_POINT('',(12.3124784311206,0.527755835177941,-1.95198936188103));
#620=CARTESIAN_POINT('',(12.2821989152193,0.728658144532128,-1.88620214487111));
#621=CARTESIAN_POINT('',(12.2638221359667,0.825883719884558,-1.84564418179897));
#622=CARTESIAN_POINT('',(12.2222578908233,1.01202231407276,-1.75051924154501));
#623=CARTESIAN_POINT('',(12.1990710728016,1.10093645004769,-1.69595415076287));
#624=CARTESIAN_POINT('',(12.1485066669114,1.27361832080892,-1.57082016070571));
#625=CARTESIAN_POINT('',(12.1209657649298,1.35680605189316,-1.49951775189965));
#626=CARTESIAN_POINT('',(12.0653733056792,1.51056872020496,-1.34450262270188));
#627=CARTESIAN_POINT('',(12.0373214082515,1.58113489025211,-1.26078134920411));
#628=CARTESIAN_POINT('',(11.9816498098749,1.7125586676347,-1.07629586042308));
#629=CARTESIAN_POINT('',(11.9541960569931,1.7723988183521,-0.974751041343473));
#630=CARTESIAN_POINT('',(11.9055283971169,1.87389933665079,-0.761566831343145));
#631=CARTESIAN_POINT('',(11.8843103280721,1.91557183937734,-0.649934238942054));
#632=CARTESIAN_POINT('',(11.8523398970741,1.97698392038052,-0.426331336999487));
#633=CARTESIAN_POINT('',(11.8410563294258,1.99784596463,-0.314748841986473));
#634=CARTESIAN_POINT('',(11.8287790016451,2.02050711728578,-0.0891428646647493));
#635=CARTESIAN_POINT('',(11.8277764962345,2.02232242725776,0.024878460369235));
#636=CARTESIAN_POINT('',(11.835740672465,2.00766665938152,0.238980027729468));
#637=CARTESIAN_POINT('',(11.843647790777,1.99313940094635,0.339241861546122));
#638=CARTESIAN_POINT('',(11.8667010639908,1.9495499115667,0.535681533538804));
#639=CARTESIAN_POINT('',(11.8818492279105,1.92048364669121,0.631858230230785));
#640=CARTESIAN_POINT('',(11.9180243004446,1.84808217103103,0.820108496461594));
#641=CARTESIAN_POINT('',(11.9391797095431,1.80443089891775,0.912034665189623));
#642=CARTESIAN_POINT('',(11.9849808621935,1.70433373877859,1.08768048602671));
#643=CARTESIAN_POINT('',(12.0096281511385,1.64788217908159,1.17139647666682));
#644=CARTESIAN_POINT('',(12.0630694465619,1.51619938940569,1.33838656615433));
#645=CARTESIAN_POINT('',(12.0920142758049,1.43955472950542,1.42050154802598));
#646=CARTESIAN_POINT('',(12.1484663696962,1.27341129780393,1.57117111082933));
#647=CARTESIAN_POINT('',(12.1759730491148,1.1839073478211,1.63972020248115));
#648=CARTESIAN_POINT('',(12.2277795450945,0.990088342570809,1.76381495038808));
#649=CARTESIAN_POINT('',(12.2519106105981,0.885329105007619,1.81874288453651));
#650=CARTESIAN_POINT('',(12.2928537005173,0.666605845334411,1.90976726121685));
#651=CARTESIAN_POINT('',(12.3096710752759,0.552648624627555,1.94587747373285));
#652=CARTESIAN_POINT('',(12.3329916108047,0.328309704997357,1.99547875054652));
#653=CARTESIAN_POINT('',(12.3401974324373,0.218343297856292,2.01051544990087));
#654=CARTESIAN_POINT('',(12.3458467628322,-0.00277260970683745,2.02232712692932));
#655=CARTESIAN_POINT('',(12.3442939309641,-0.113921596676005,2.0191097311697));
#656=CARTESIAN_POINT('',(12.3330254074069,-0.326023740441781,1.99546315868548));
#657=CARTESIAN_POINT('',(12.3238866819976,-0.427147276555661,1.97625026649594));
#658=CARTESIAN_POINT('',(12.2990742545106,-0.624556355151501,1.92300728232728));
#659=CARTESIAN_POINT('',(12.2833998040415,-0.720841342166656,1.88897549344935));
#660=CARTESIAN_POINT('',(12.2463664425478,-0.909163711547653,1.80607296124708));
#661=CARTESIAN_POINT('',(12.2248507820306,-1.00098632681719,1.75678680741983));
#662=CARTESIAN_POINT('',(12.1782688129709,-1.17537718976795,1.64523197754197));
#663=CARTESIAN_POINT('',(12.1532009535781,-1.25794136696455,1.58295762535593));
#664=CARTESIAN_POINT('',(12.0992710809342,-1.41948396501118,1.44057879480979));
#665=CARTESIAN_POINT('',(12.0702719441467,-1.49743912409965,1.35936289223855));
#666=CARTESIAN_POINT('',(12.013541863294,-1.63903132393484,1.18481538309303));
#667=CARTESIAN_POINT('',(11.9858116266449,-1.70266045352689,1.09147712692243));
#668=CARTESIAN_POINT('',(11.9338112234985,-1.81600503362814,0.890769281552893));
#669=CARTESIAN_POINT('',(11.9097123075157,-1.86510080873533,0.78300162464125));
#670=CARTESIAN_POINT('',(11.8698056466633,-1.94394019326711,0.559196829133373));
#671=CARTESIAN_POINT('',(11.8539881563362,-1.9737065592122,0.443169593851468));
#672=CARTESIAN_POINT('',(11.8342677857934,-2.01047355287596,0.217679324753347));
#673=CARTESIAN_POINT('',(11.8293967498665,-2.01932799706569,0.108604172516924));
#674=CARTESIAN_POINT('',(11.8294288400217,-2.01927189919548,-0.109523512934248));
#675=CARTESIAN_POINT('',(11.8343287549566,-2.01036719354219,-0.218576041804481));
#676=CARTESIAN_POINT('',(11.8523574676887,-1.97674011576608,-0.424338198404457));
#677=CARTESIAN_POINT('',(11.8647906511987,-1.95335151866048,-0.521333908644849));
#678=CARTESIAN_POINT('',(11.8957350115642,-1.89297275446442,-0.709957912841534));
#679=CARTESIAN_POINT('',(11.9142480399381,-1.85597844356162,-0.80158456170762));
#680=CARTESIAN_POINT('',(11.9567879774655,-1.76663819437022,-0.98362755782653));
#681=CARTESIAN_POINT('',(11.9811010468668,-1.71343032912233,-1.07355223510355));
#682=CARTESIAN_POINT('',(12.0319461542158,-1.59418732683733,-1.2437641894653));
#683=CARTESIAN_POINT('',(12.0584792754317,-1.52814590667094,-1.32404671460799));
#684=CARTESIAN_POINT('',(12.1142040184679,-1.37673061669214,-1.48168072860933));
#685=CARTESIAN_POINT('',(12.1433736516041,-1.29003977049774,-1.5577817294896));
#686=CARTESIAN_POINT('',(12.1983964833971,-1.10421108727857,-1.69457937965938));
#687=CARTESIAN_POINT('',(12.2242480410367,-1.00506713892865,-1.75526842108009));
#688=CARTESIAN_POINT('',(12.2697969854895,-0.796801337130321,-1.85908628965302));
#689=CARTESIAN_POINT('',(12.2895022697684,-0.687692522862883,-1.90223767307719));
#690=CARTESIAN_POINT('',(12.3204605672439,-0.462707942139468,-1.96905011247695));
#691=CARTESIAN_POINT('',(12.3317383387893,-0.346853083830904,-1.99276827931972));
#692=CARTESIAN_POINT('',(12.3402176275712,-0.191644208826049,-2.0105538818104));
#693=CARTESIAN_POINT('',(12.3417825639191,-0.153411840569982,-2.0138297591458));
#694=CARTESIAN_POINT('',(12.343874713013,-0.07679248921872,-2.01820396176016));
#695=CARTESIAN_POINT('',(12.3444019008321,-0.038405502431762,-2.01930223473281));
#696=CARTESIAN_POINT('',(12.3444,0.,-2.01929999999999));
#697=B_SPLINE_CURVE_WITH_KNOTS('',3,(#615,#616,#617,#618,#619,#620,#621,#622,#623,#624,#625,
#626,#627,#628,#629,#630,#631,#632,#633,#634,#635,#636,#637,#638,#639,#640,#641,#642,#643,#644,
#645,#646,#647,#648,#649,#650,#651,#652,#653,#654,#655,#656,#657,#658,#659,#660,#661,#662,#663,
#664,#665,#666,#667,#668,#669,#670,#671,#672,#673,#674,#675,#676,#677,#678,#679,#680,#681,#682,
#683,#684,#685,#686,#687,#688,#689,#690,#691,#692,#693,#694,#695,#696),.UNSPECIFIED.,.T.,.F.,(4,
2,2,2,2,2,2,2,2,2,2,2,2,2,2,2,2,2,2,2,2,2,2,2,2,2,2,2,2,2,2,2,2,2,2,2,2,2,2,2,4),(0.,
0.319907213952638,0.640488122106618,0.959866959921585,1.27920280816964,1.61669430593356,
1.95441932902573,2.31564840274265,2.67663582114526,3.01688536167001,3.35684545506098,
3.66027862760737,3.96379603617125,4.27437070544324,4.58508325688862,4.93154597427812,
5.27814859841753,5.63838803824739,5.99836349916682,6.3302389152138,6.6619756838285,
6.97057174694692,7.27920315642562,7.59711450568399,7.91516508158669,8.26238386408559,
8.60979392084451,8.97038842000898,9.33055761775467,9.65735534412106,9.98404568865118,
10.284385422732,10.5848167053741,10.905360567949,11.2260617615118,11.5813594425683,
11.9368321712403,12.2918462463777,12.6458132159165,12.7609706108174,12.8761307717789),.UNSPECIFIED.);
#698=CARTESIAN_POINT('',(12.3444,0.,-2.01929999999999));
#699=VERTEX_POINT('',#698);
#700=EDGE_CURVE('E212',#699,#699,#697,.T.);
#701=ORIENTED_EDGE('',*,*,#700,.T.);
#702=EDGE_LOOP('',(#701));
#703=FACE_BOUND('',#702,.T.);
#704=CARTESIAN_POINT('',(8.128,0.,4.18846));
#705=DIRECTION('',(0.,0.,1.));
#706=DIRECTION('',(1.,0.,0.));
#707=AXIS2_PLACEMENT_3D('',#704,#705,#706);
#708=CIRCLE('',#707,4.2164);
#709=CARTESIAN_POINT('',(12.3444,0.,4.18846));
#710=VERTEX_POINT('',#709);
#711=EDGE_CURVE('E485',#710,#710,#708,.T.);
#712=ORIENTED_EDGE('',*,*,#711,.T.);
#713=EDGE_LOOP('',(#712));
#714=FACE_BOUND('',#713,.T.);
#715=CARTESIAN_POINT('',(8.128,0.,-4.18846));
#716=DIRECTION('',(0.,0.,-1.));
#717=DIRECTION('',(-1.,0.,0.));
#718=AXIS2_PLACEMENT_3D('',#715,#716,#717);
#719=CIRCLE('',#718,4.2164);
#720=CARTESIAN_POINT('',(3.9116,0.,-4.18846));
#721=VERTEX_POINT('',#720);
#722=EDGE_CURVE('E269',#721,#721,#719,.T.);
#723=ORIENTED_EDGE('',*,*,#722,.T.);
#724=EDGE_LOOP('',(#723));
#725=FACE_BOUND('',#724,.T.);
#726=ADVANCED_FACE('F221',(#703,#714,#725),#614,.F.);
#727=CARTESIAN_POINT('',(12.3444,0.,-4.18846));
#728=DIRECTION('',(0.,0.,1.));
#729=DIRECTION('',(1.,0.,0.));
#730=AXIS2_PLACEMENT_3D('',#727,#728,#729);
#731=PLANE('',#730);
#732=ORIENTED_EDGE('',*,*,#722,.F.);
#733=EDGE_LOOP('',(#732));
#734=FACE_BOUND('',#733,.T.);
#735=CARTESIAN_POINT('',(8.128,0.,-4.18846));
#736=DIRECTION('',(0.,0.,-1.));
#737=DIRECTION('',(-1.,0.,0.));
#738=AXIS2_PLACEMENT_3D('',#735,#736,#737);
#739=CIRCLE('',#738,5.10912086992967);
#740=CARTESIAN_POINT('',(3.01887913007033,0.,-4.18846));
#741=VERTEX_POINT('',#740);
#742=EDGE_CURVE('E468',#741,#741,#739,.T.);
#743=ORIENTED_EDGE('',*,*,#742,.T.);
#744=EDGE_LOOP('',(#743));
#745=FACE_BOUND('',#744,.T.);
#746=ADVANCED_FACE('F225',(#734,#745),#731,.F.);
#747=CARTESIAN_POINT('',(8.128,0.,-11.1125));
#748=DIRECTION('',(0.,0.,-1.));
#749=DIRECTION('',(-1.,0.,0.));
#750=AXIS2_PLACEMENT_3D('',#747,#748,#749);
#751=CONICAL_SURFACE('',#750,5.3164359,0.0299323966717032);
#752=ORIENTED_EDGE('',*,*,#742,.F.);
#753=EDGE_LOOP('',(#752));
#754=FACE_BOUND('',#753,.T.);
#755=ORIENTED_EDGE('',*,*,#276,.T.);
#756=EDGE_LOOP('',(#755));
#757=FACE_BOUND('',#756,.T.);
#758=ADVANCED_FACE('F379',(#754,#757),#751,.F.);
#759=CARTESIAN_POINT('',(25.4,0.,-4.7625));
#760=DIRECTION('',(0.,0.,1.));
#761=DIRECTION('',(1.,0.,0.));
#762=AXIS2_PLACEMENT_3D('',#759,#760,#761);
#763=CONICAL_SURFACE('',#762,4.2164,1.02974425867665);
#764=CARTESIAN_POINT('',(25.4,0.,-7.29596871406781));
#765=VERTEX_POINT('',#764);
#766=VERTEX_LOOP('',#765);
#767=FACE_BOUND('',#766,.T.);
#768=CARTESIAN_POINT('',(25.4,0.,-4.7625));
#769=DIRECTION('',(0.,0.,1.));
#770=DIRECTION('',(1.,0.,0.));
#771=AXIS2_PLACEMENT_3D('',#768,#769,#770);
#772=CIRCLE('',#771,4.2164);
#773=CARTESIAN_POINT('',(29.6164,0.,-4.7625));
#774=VERTEX_POINT('',#773);
#775=EDGE_CURVE('E475',#774,#774,#772,.T.);
#776=ORIENTED_EDGE('',*,*,#775,.T.);
#777=EDGE_LOOP('',(#776));
#778=FACE_BOUND('',#777,.T.);
#779=ADVANCED_FACE('F174',(#767,#778),#763,.F.);
#780=CARTESIAN_POINT('',(25.4,0.,11.1125));
#781=DIRECTION('',(0.,0.,1.));
#782=DIRECTION('',(1.,0.,0.));
#783=AXIS2_PLACEMENT_3D('',#780,#781,#782);
#784=CYLINDRICAL_SURFACE('',#783,4.2164);
#785=CARTESIAN_POINT('',(21.1836,0.,-2.38124999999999));
#786=CARTESIAN_POINT('',(21.1836087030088,-0.123213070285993,-2.38124016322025));
#787=CARTESIAN_POINT('',(21.1890570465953,-0.246543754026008,-2.37162838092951));
#788=CARTESIAN_POINT('',(21.2103067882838,-0.489274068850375,-2.33368546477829));
#789=CARTESIAN_POINT('',(21.226108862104,-0.60867344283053,-2.30535310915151));
#790=CARTESIAN_POINT('',(21.2664430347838,-0.839919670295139,-2.23149430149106));
#791=CARTESIAN_POINT('',(21.29094284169,-0.951792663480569,-2.18603141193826));
#792=CARTESIAN_POINT('',(21.3465413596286,-1.16609583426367,-2.07964023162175));
#793=CARTESIAN_POINT('',(21.3776417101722,-1.26852365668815,-2.01870809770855));
#794=CARTESIAN_POINT('',(21.4463244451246,-1.46918570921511,-1.87826825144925));
#795=CARTESIAN_POINT('',(21.4842102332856,-1.56660625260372,-1.79774904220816));
#796=CARTESIAN_POINT('',(21.5614456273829,-1.74734348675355,-1.62265201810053));
#797=CARTESIAN_POINT('',(21.6007967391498,-1.83064515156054,-1.52805942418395));
#798=CARTESIAN_POINT('',(21.6813991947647,-1.98967106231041,-1.31566490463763));
#799=CARTESIAN_POINT('',(21.7224124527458,-2.06366647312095,-1.19646694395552));
#800=CARTESIAN_POINT('',(21.7963552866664,-2.19024613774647,-0.944942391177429));
#801=CARTESIAN_POINT('',(21.8292967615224,-2.2428619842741,-0.812635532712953));
#802=CARTESIAN_POINT('',(21.8759135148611,-2.315227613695,-0.568010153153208));
#803=CARTESIAN_POINT('',(21.8922162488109,-2.33962741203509,-0.457568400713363));
#804=CARTESIAN_POINT('',(21.9143525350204,-2.37248842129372,-0.233351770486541));
#805=CARTESIAN_POINT('',(21.9201969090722,-2.38096610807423,-0.119580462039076));
#806=CARTESIAN_POINT('',(21.9205761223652,-2.3815202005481,0.10815955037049));
#807=CARTESIAN_POINT('',(21.9150968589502,-2.3735761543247,0.222128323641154));
#808=CARTESIAN_POINT('',(21.8936094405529,-2.34171049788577,0.44680968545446));
#809=CARTESIAN_POINT('',(21.8775942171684,-2.31777816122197,0.557520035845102));
#810=CARTESIAN_POINT('',(21.837188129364,-2.25516473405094,0.772742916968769));
#811=CARTESIAN_POINT('',(21.8128146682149,-2.21651427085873,0.877267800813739));
#812=CARTESIAN_POINT('',(21.758322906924,-2.12579662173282,1.07868270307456));
#813=CARTESIAN_POINT('',(21.7282023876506,-2.07372425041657,1.17556975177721));
#814=CARTESIAN_POINT('',(21.6598913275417,-1.94819888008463,1.37508390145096));
#815=CARTESIAN_POINT('',(21.6211759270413,-1.87267377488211,1.47622950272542));
#816=CARTESIAN_POINT('',(21.5433627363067,-1.7066901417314,1.66535612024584));
#817=CARTESIAN_POINT('',(21.5042646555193,-1.6162192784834,1.75332614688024));
#818=CARTESIAN_POINT('',(21.4250672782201,-1.41112679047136,1.92318941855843));
#819=CARTESIAN_POINT('',(21.3853195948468,-1.29494987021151,2.00338781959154));
#820=CARTESIAN_POINT('',(21.3139875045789,-1.04831503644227,2.14275688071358));
#821=CARTESIAN_POINT('',(21.2823978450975,-0.917866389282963,2.20194108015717));
#822=CARTESIAN_POINT('',(21.2329340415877,-0.655818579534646,2.29305882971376));
#823=CARTESIAN_POINT('',(21.214254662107,-0.524939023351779,2.32660979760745));
#824=CARTESIAN_POINT('',(21.1893947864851,-0.258268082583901,2.37104844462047));
#825=CARTESIAN_POINT('',(21.1832025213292,-0.122481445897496,2.38195746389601));
#826=CARTESIAN_POINT('',(21.1839893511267,0.132835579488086,2.38055735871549));
#827=CARTESIAN_POINT('',(21.189501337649,0.252394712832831,2.37083450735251));
#828=CARTESIAN_POINT('',(21.21025284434,0.48786607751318,2.33378239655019));
#829=CARTESIAN_POINT('',(21.2254925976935,0.603778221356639,2.30645271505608));
#830=CARTESIAN_POINT('',(21.2641629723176,0.828105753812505,2.23569601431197));
#831=CARTESIAN_POINT('',(21.287532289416,0.936570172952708,2.19238933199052));
#832=CARTESIAN_POINT('',(21.3405604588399,1.14478700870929,2.09122579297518));
#833=CARTESIAN_POINT('',(21.3702208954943,1.24453722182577,2.03336527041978));
#834=CARTESIAN_POINT('',(21.4369094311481,1.44363259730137,1.89795652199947));
#835=CARTESIAN_POINT('',(21.4743826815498,1.5418616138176,1.81898836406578));
#836=CARTESIAN_POINT('',(21.5510807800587,1.7244356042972,1.64694711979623));
#837=CARTESIAN_POINT('',(21.5903075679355,1.80876469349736,1.55385812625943));
#838=CARTESIAN_POINT('',(21.6710734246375,1.97031210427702,1.34444585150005));
#839=CARTESIAN_POINT('',(21.7124107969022,2.04580407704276,1.22670227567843));
#840=CARTESIAN_POINT('',(21.7875124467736,2.17568797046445,0.977931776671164));
#841=CARTESIAN_POINT('',(21.8212870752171,2.23010880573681,0.846923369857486));
#842=CARTESIAN_POINT('',(21.8699859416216,2.30621422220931,0.60362375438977));
#843=CARTESIAN_POINT('',(21.8873862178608,2.33238814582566,0.4932341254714));
#844=CARTESIAN_POINT('',(21.9118020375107,2.36875540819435,0.268773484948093));
#845=CARTESIAN_POINT('',(21.9188287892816,2.37896599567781,0.154706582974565));
#846=CARTESIAN_POINT('',(21.9214860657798,2.38285073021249,-0.0740359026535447));
#847=CARTESIAN_POINT('',(21.9170975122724,2.37649719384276,-0.188712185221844));
#848=CARTESIAN_POINT('',(21.8975411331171,2.34757335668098,-0.41507892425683));
#849=CARTESIAN_POINT('',(21.882366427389,2.3249927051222,-0.526767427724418));
#850=CARTESIAN_POINT('',(21.8435048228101,2.26508560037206,-0.743109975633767));
#851=CARTESIAN_POINT('',(21.8199138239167,2.22792482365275,-0.847828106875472));
#852=CARTESIAN_POINT('',(21.7667785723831,2.14017650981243,-1.04982755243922));
#853=CARTESIAN_POINT('',(21.737232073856,2.08958390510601,-1.14710604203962));
#854=CARTESIAN_POINT('',(21.6700332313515,1.96746979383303,-1.34728752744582));
#855=CARTESIAN_POINT('',(21.6318322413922,1.893931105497,-1.44877661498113));
#856=CARTESIAN_POINT('',(21.5547176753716,1.73201617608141,-1.63892683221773));
#857=CARTESIAN_POINT('',(21.5158035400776,1.64362780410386,-1.72757736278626));
#858=CARTESIAN_POINT('',(21.4363245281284,1.44233420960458,-1.89988107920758));
#859=CARTESIAN_POINT('',(21.3960893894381,1.32777570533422,-1.98177002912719));
#860=CARTESIAN_POINT('',(21.3233598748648,1.08403185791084,-2.1248819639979));
#861=CARTESIAN_POINT('',(21.2908620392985,0.954853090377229,-2.18611419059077));
#862=CARTESIAN_POINT('',(21.251300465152,0.755467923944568,-2.25929544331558));
#863=CARTESIAN_POINT('',(21.2397801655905,0.689360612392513,-2.28034592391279));
#864=CARTESIAN_POINT('',(21.2197572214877,0.555147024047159,-2.31667561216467));
#865=CARTESIAN_POINT('',(21.2112529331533,0.48704185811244,-2.3319579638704));
#866=CARTESIAN_POINT('',(21.1975391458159,0.349466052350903,-2.35650242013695));
#867=CARTESIAN_POINT('',(21.1923277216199,0.279996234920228,-2.36576804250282));
#868=CARTESIAN_POINT('',(21.1853558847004,0.140363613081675,-2.37814425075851));
#869=CARTESIAN_POINT('',(21.1835950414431,0.0702008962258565,-2.38125560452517));
#870=CARTESIAN_POINT('',(21.1836,0.,-2.38124999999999));
#871=B_SPLINE_CURVE_WITH_KNOTS('',3,(#785,#786,#787,#788,#789,#790,#791,#792,#793,#794,#795,
#796,#797,#798,#799,#800,#801,#802,#803,#804,#805,#806,#807,#808,#809,#810,#811,#812,#813,#814,
#815,#816,#817,#818,#819,#820,#821,#822,#823,#824,#825,#826,#827,#828,#829,#830,#831,#832,#833,
#834,#835,#836,#837,#838,#839,#840,#841,#842,#843,#844,#845,#846,#847,#848,#849,#850,#851,#852,
#853,#854,#855,#856,#857,#858,#859,#860,#861,#862,#863,#864,#865,#866,#867,#868,#869,#870),
.UNSPECIFIED.,.T.,.F.,(4,2,2,2,2,2,2,2,2,2,2,2,2,2,2,2,2,2,2,2,2,2,2,2,2,2,2,2,2,2,2,2,2,2,2,2,
2,2,2,2,2,2,4),(0.,0.369364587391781,0.738753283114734,1.1067846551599,1.47490754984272,
1.86915937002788,2.2638281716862,2.70016980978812,3.13586429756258,3.47719912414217,
3.81818054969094,4.15958689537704,4.50122251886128,4.84215107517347,5.18321154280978,
5.57774270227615,5.97260112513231,6.41030024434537,6.84771684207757,7.25451716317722,
7.66093389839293,8.01942438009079,8.37792345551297,8.73377571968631,9.08971770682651,
9.48259549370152,9.87591919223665,10.3113287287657,10.7461386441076,11.0889866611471,
11.4314639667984,11.7745140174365,12.1177830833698,12.4572595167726,12.7968642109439,
13.1883899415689,13.5802370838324,14.0174105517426,14.4543881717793,14.665098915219,
14.8756946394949,15.0861671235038,15.2966133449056),.UNSPECIFIED.);
#872=CARTESIAN_POINT('',(21.1836,0.,-2.38124999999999));
#873=VERTEX_POINT('',#872);
#874=EDGE_CURVE('E189',#873,#873,#871,.T.);
#875=ORIENTED_EDGE('',*,*,#874,.T.);
#876=EDGE_LOOP('',(#875));
#877=FACE_BOUND('',#876,.T.);
#878=ORIENTED_EDGE('',*,*,#591,.T.);
#879=CARTESIAN_POINT('',(25.4,0.,4.18846));
#880=DIRECTION('',(0.,0.,1.));
#881=DIRECTION('',(1.,0.,0.));
#882=AXIS2_PLACEMENT_3D('',#879,#880,#881);
#883=CIRCLE('',#882,4.2164);
#884=EDGE_CURVE('E51',#549,#506,#883,.T.);
#885=ORIENTED_EDGE('',*,*,#884,.T.);
#886=ORIENTED_EDGE('',*,*,#507,.T.);
#887=ORIENTED_EDGE('',*,*,#604,.T.);
#888=ORIENTED_EDGE('',*,*,#462,.T.);
#889=ORIENTED_EDGE('',*,*,#32,.T.);
#890=EDGE_LOOP('',(#878,#885,#886,#887,#888,#889));
#891=FACE_BOUND('',#890,.T.);
#892=ORIENTED_EDGE('',*,*,#775,.F.);
#893=EDGE_LOOP('',(#892));
#894=FACE_BOUND('',#893,.T.);
#895=ADVANCED_FACE('F168',(#877,#891,#894),#784,.F.);
#896=CARTESIAN_POINT('',(29.6164,0.,4.18846));
#897=DIRECTION('',(0.,0.,-1.));
#898=DIRECTION('',(-1.,0.,0.));
#899=AXIS2_PLACEMENT_3D('',#896,#897,#898);
#900=PLANE('',#899);
#901=ORIENTED_EDGE('',*,*,#515,.T.);
#902=ORIENTED_EDGE('',*,*,#884,.F.);
#903=ORIENTED_EDGE('',*,*,#550,.T.);
#904=CARTESIAN_POINT('',(25.4,0.,4.18846));
#905=DIRECTION('',(0.,0.,1.));
#906=DIRECTION('',(1.,0.,0.));
#907=AXIS2_PLACEMENT_3D('',#904,#905,#906);
#908=CIRCLE('',#907,4.93618496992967);
#909=EDGE_CURVE('E479',#541,#514,#908,.T.);
#910=ORIENTED_EDGE('',*,*,#909,.T.);
#911=EDGE_LOOP('',(#901,#902,#903,#910));
#912=FACE_BOUND('',#911,.T.);
#913=ADVANCED_FACE('F173',(#912),#900,.F.);
#914=CARTESIAN_POINT('',(25.4,0.,11.1125));
#915=DIRECTION('',(0.,0.,1.));
#916=DIRECTION('',(1.,0.,0.));
#917=AXIS2_PLACEMENT_3D('',#914,#915,#916);
#918=CONICAL_SURFACE('',#917,5.1435,0.0299323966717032);
#919=ORIENTED_EDGE('',*,*,#542,.T.);
#920=ORIENTED_EDGE('',*,*,#909,.F.);
#921=EDGE_LOOP('',(#919,#920));
#922=FACE_BOUND('',#921,.T.);
#923=ORIENTED_EDGE('',*,*,#193,.T.);
#924=EDGE_LOOP('',(#923));
#925=FACE_BOUND('',#924,.T.);
#926=ADVANCED_FACE('F391',(#922,#925),#918,.F.);
#927=CARTESIAN_POINT('',(12.3444,0.,4.18846));
#928=DIRECTION('',(0.,0.,-1.));
#929=DIRECTION('',(-1.,0.,0.));
#930=AXIS2_PLACEMENT_3D('',#927,#928,#929);
#931=PLANE('',#930);
#932=ORIENTED_EDGE('',*,*,#711,.F.);
#933=EDGE_LOOP('',(#932));
#934=FACE_BOUND('',#933,.T.);
#935=CARTESIAN_POINT('',(8.128,0.,4.18846));
#936=DIRECTION('',(0.,0.,1.));
#937=DIRECTION('',(1.,0.,0.));
#938=AXIS2_PLACEMENT_3D('',#935,#936,#937);
#939=CIRCLE('',#938,4.93618496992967);
#940=CARTESIAN_POINT('',(13.0641849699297,0.,4.18846));
#941=VERTEX_POINT('',#940);
#942=EDGE_CURVE('E487',#941,#941,#939,.T.);
#943=ORIENTED_EDGE('',*,*,#942,.T.);
#944=EDGE_LOOP('',(#943));
#945=FACE_BOUND('',#944,.T.);
#946=ADVANCED_FACE('F400',(#934,#945),#931,.F.);
#947=CARTESIAN_POINT('',(8.128,0.,11.1125));
#948=DIRECTION('',(0.,0.,1.));
#949=DIRECTION('',(1.,0.,0.));
#950=AXIS2_PLACEMENT_3D('',#947,#948,#949);
#951=CONICAL_SURFACE('',#950,5.1435,0.0299323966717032);
#952=ORIENTED_EDGE('',*,*,#942,.F.);
#953=EDGE_LOOP('',(#952));
#954=FACE_BOUND('',#953,.T.);
#955=ORIENTED_EDGE('',*,*,#182,.T.);
#956=EDGE_LOOP('',(#955));
#957=FACE_BOUND('',#956,.T.);
#958=ADVANCED_FACE('F208',(#954,#957),#951,.F.);
#959=CARTESIAN_POINT('',(41.275,0.,0.));
#960=DIRECTION('',(1.,0.,0.));
#961=DIRECTION('',(0.,0.,-1.));
#962=AXIS2_PLACEMENT_3D('',#959,#960,#961);
#963=CYLINDRICAL_SURFACE('',#962,2.01929999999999);
#964=CARTESIAN_POINT('',(18.832518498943,0.,0.));
#965=DIRECTION('',(1.,0.,0.));
#966=DIRECTION('',(0.,0.,-1.));
#967=AXIS2_PLACEMENT_3D('',#964,#965,#966);
#968=CIRCLE('',#967,2.01929999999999);
#969=CARTESIAN_POINT('',(18.832518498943,0.,-2.01929999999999));
#970=VERTEX_POINT('',#969);
#971=EDGE_CURVE('E38',#970,#970,#968,.T.);
#972=ORIENTED_EDGE('',*,*,#971,.T.);
#973=EDGE_LOOP('',(#972));
#974=FACE_BOUND('',#973,.T.);
#975=ORIENTED_EDGE('',*,*,#700,.F.);
#976=EDGE_LOOP('',(#975));
#977=FACE_BOUND('',#976,.T.);
#978=ADVANCED_FACE('F203',(#974,#977),#963,.F.);
#979=CARTESIAN_POINT('',(19.05,0.,0.));
#980=DIRECTION('',(1.,0.,0.));
#981=DIRECTION('',(0.,0.,-1.));
#982=AXIS2_PLACEMENT_3D('',#979,#980,#981);
#983=CONICAL_SURFACE('',#982,2.38124999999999,1.02974425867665);
#984=CARTESIAN_POINT('',(19.05,0.,0.));
#985=DIRECTION('',(1.,0.,0.));
#986=DIRECTION('',(0.,0.,-1.));
#987=AXIS2_PLACEMENT_3D('',#984,#985,#986);
#988=CIRCLE('',#987,2.38124999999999);
#989=CARTESIAN_POINT('',(19.05,0.,-2.38124999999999));
#990=VERTEX_POINT('',#989);
#991=EDGE_CURVE('E194',#990,#990,#988,.T.);
#992=ORIENTED_EDGE('',*,*,#991,.T.);
#993=EDGE_LOOP('',(#992));
#994=FACE_BOUND('',#993,.T.);
#995=ORIENTED_EDGE('',*,*,#971,.F.);
#996=EDGE_LOOP('',(#995));
#997=FACE_BOUND('',#996,.T.);
#998=ADVANCED_FACE('F199',(#994,#997),#983,.F.);
#999=CARTESIAN_POINT('',(41.275,0.,0.));
#1000=DIRECTION('',(1.,0.,0.));
#1001=DIRECTION('',(0.,0.,-1.));
#1002=AXIS2_PLACEMENT_3D('',#999,#1000,#1001);
#1003=CYLINDRICAL_SURFACE('',#1002,2.38124999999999);
#1004=ORIENTED_EDGE('',*,*,#991,.F.);
#1005=EDGE_LOOP('',(#1004));
#1006=FACE_BOUND('',#1005,.T.);
#1007=ORIENTED_EDGE('',*,*,#874,.F.);
#1008=EDGE_LOOP('',(#1007));
#1009=FACE_BOUND('',#1008,.T.);
#1010=ADVANCED_FACE('F195',(#1006,#1009),#1003,.F.);
#1011=CLOSED_SHELL('',(#43,#71,#138,#169,#215,#239,#263,#298,#315,#329,#341,#361,#381,#599,#609,
#726,#746,#758,#779,#895,#913,#926,#946,#958,#978,#998,#1010));
#1012=MANIFOLD_SOLID_BREP('B2',#1011);
#1013=ADVANCED_BREP_SHAPE_REPRESENTATION('',(#18,#1012),#14);
#1014=SHAPE_DEFINITION_REPRESENTATION(#9,#1013);
ENDSEC;
END-ISO-10303-21;
